! (c) 2009  Infineon Technologies AG, Munich
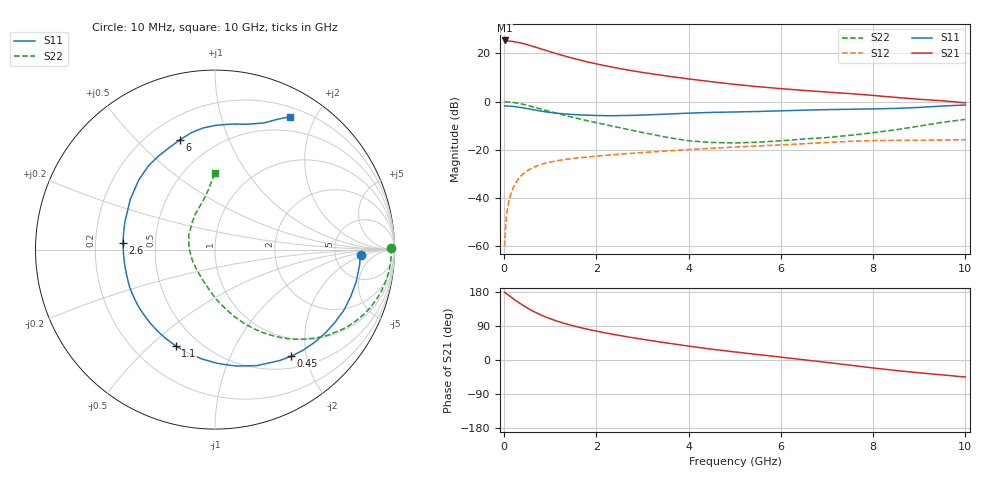
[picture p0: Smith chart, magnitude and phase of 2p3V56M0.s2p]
! Infineon Technologies  Discrete & RF Semiconductors
! BFP420
! VCE =  3.5 V,  IC =  6.0 mA
! Common Emitter S-Parameters:  Nov 2009
# GHz  S  MA  R  50
!  f  S11  S21  S12  S22
! GHz  MAG  ANG  MAG  ANG  MAG  ANG  MAG  ANG
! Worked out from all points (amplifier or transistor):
!   46 points, 10 MHz to 10 GHz, reference 50 ohm
!   highest |S21| = 25.4 dB at 10 MHz (marker M1)
!   |S21| within 3 dB of that: start of sweep to 718.3 MHz
!   unconditionally stable (mu >= 1): start of sweep to 10.25 MHz; 2.84 GHz to end of sweep
!   at 300 MHz: K = 0.14, MSG = 28.4 dB, |S12| = -32.3 dB
!   at 1.7 GHz: K = 0.65, MSG = 20.1 dB, |S12| = -23.2 dB
!   at 10 GHz: K = 1.11, MAG = 5.6 dB, |S12| = -15.8 dB
!   lowest NFmin = 0.70 dB at 900 MHz
!   S11 on the Smith chart (normalised r, x): 10 MHz: 9.36, -1.55; 450 MHz: 0.68, -1.74; 1.1 GHz: 0.37, -0.60; 2.6 GHz: 0.32, +0.03; 6 GHz: 0.33, +0.68; 10 GHz: 0.31, +1.67
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0.01  0.8116 -2.0  18.54 179.0  0.001 37.5  0.9787 0.5
0.02  0.8099 -2.4  18.08 178.0  0.0018 70.0  0.9819 -1.4
0.1  0.8071 -12.7  18.03 170.5  0.0085 80.5  0.9768 -7.1
0.2  0.7939 -25.1  17.59 161.6  0.0166 75.7  0.9555 -14.0
0.25  0.7816 -31.3  17.22 157.1  0.0205 73.1  0.9408 -17.3
0.35  0.7572 -43.3  16.51 148.9  0.0277 67.9  0.9032 -23.7
0.45  0.7304 -54.5  15.64 141.1  0.0339 63.0  0.8597 -29.5
0.6  0.687 -70.2  14.23 130.6  0.0418 56.6  0.7894 -37.2
0.7  0.6594 -79.8  13.3 124.4  0.046 53.1  0.7433 -41.6
0.9  0.6134 -97.0  11.57 113.5  0.0529 47.3  0.6581 -49.3
1.1  0.5795 -112.2  10.1 104.6  0.0581 43.1  0.5843 -55.6
1.4  0.5461 -131.4  8.35 93.3  0.0642 38.4  0.4934 -63.6
1.7  0.5265 -147.4  7.052 84.2  0.0693 35.2  0.4224 -70.3
2.2  0.5108 -169.3  5.519 71.4  0.0767 31.3  0.3324 -80.2
2.6  0.5144 175.6  4.667 62.6  0.0822 28.8  0.275 -88.7
3.5  0.5489 149.3  3.419 45.4  0.0941 23.9  0.183 -111.9
4.5  0.5963 128.4  2.578 28.5  0.1075 18.2  0.1417 -148.9
5.5  0.623 114.1  2.04 14.4  0.1198 12.5  0.1435 177.7
6  0.6429 107.5  1.856 7.6  0.1262 9.7  0.1539 162.7
7  0.6809 95.6  1.576 -6.5  0.1417 3.0  0.1796 139.2
8.5  0.7222 75.3  1.219 -27.8  0.1567 -11.3  0.2603 108.1
10  0.8494 60.6  0.942 -45.0  0.1622 -20.7  0.4276 90.0
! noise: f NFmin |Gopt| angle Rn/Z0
0.9  0.7  0.16  29  0.14
1.8  1.08  0.06  113  0.12
2.4  1.17  0.11  132  0.13
3  1.26  0.17  176  0.11
4  1.43  0.31  -139  0.13
5  1.82  0.38  -115  0.24
6  2.3  0.43  -99  0.37
